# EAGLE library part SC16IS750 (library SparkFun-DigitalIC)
SPI/I2C/IrDA to UART

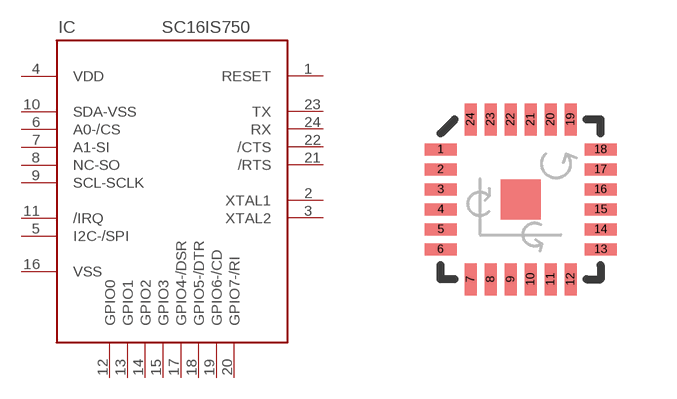
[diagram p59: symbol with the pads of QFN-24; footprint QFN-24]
Designator prefix IC

## SC16IS750  [QFN-24]
1  RESET
2  XTAL1
3  XTAL2
4  VDD
5  I2C-/SPI
6  A0-/CS
7  A1-SI
8  NC-SO
9  SCL-SCLK
10  SDA-VSS
11  /IRQ
12  GPIO0
13  GPIO1
14  GPIO2
15  GPIO3
16  VSS
17  GPIO4-/DSR
18  GPIO5-/DTR
19  GPIO6-/CD
20  GPIO7-/RI
21  /RTS
22  /CTS
23  TX
24  RX

## Footprint QFN-24 (pad centres in mm)
smd 0.8 x 0.3: 1 -2,1.25; 2 -2,0.75; 3 -2,0.25; 4 -2,-0.25; 5 -2,-0.75; 6 -2,-1.25; 13 2,-1.25; 14 2,-0.75; 15 2,-0.25; 16 2,0.25; 17 2,0.75; 18 2,1.25
smd 0.3 x 0.8: 7 -1.25,-2; 8 -0.75,-2; 9 -0.25,-2; 10 0.25,-2; 11 0.75,-2; 12 1.25,-2; 19 1.25,2; 20 0.75,2; 21 0.25,2; 22 -0.25,2; 23 -0.75,2; 24 -1.25,2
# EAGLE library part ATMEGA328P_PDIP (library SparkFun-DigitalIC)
uC used in the Arduino 32kb flash, 1k EEPROM, 2k SRAM This is the through-hole version of this chip.

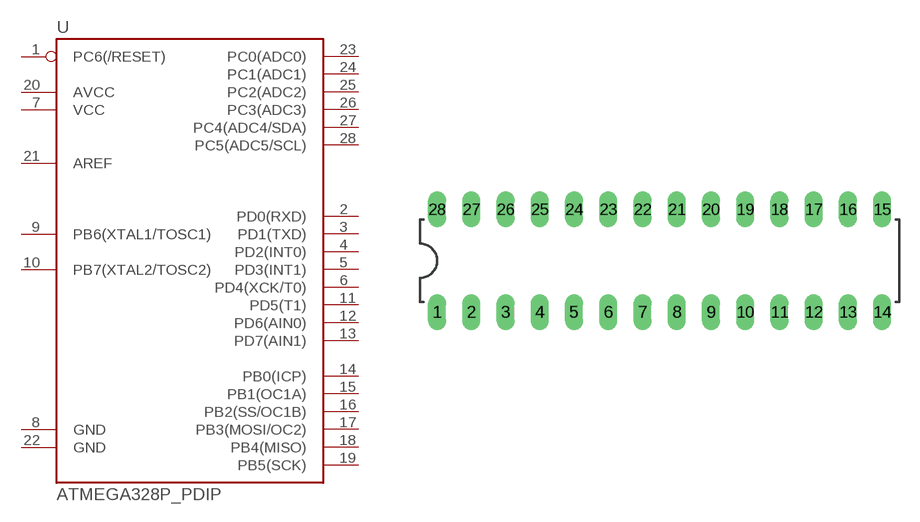
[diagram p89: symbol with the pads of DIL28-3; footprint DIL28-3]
Designator prefix U

## ATMEGA328P_PDIP  [DIL28-3]
1  PC6(/RESET)
2  PD0(RXD)
3  PD1(TXD)
4  PD2(INT0)
5  PD3(INT1)
6  PD4(XCK/T0)
7  VCC
8  GND
9  PB6(XTAL1/TOSC1)
10  PB7(XTAL2/TOSC2)
11  PD5(T1)
12  PD6(AIN0)
13  PD7(AIN1)
14  PB0(ICP)
15  PB1(OC1A)
16  PB2(SS/OC1B)
17  PB3(MOSI/OC2)
18  PB4(MISO)
19  PB5(SCK)
20  AVCC
21  AREF
22  GND
23  PC0(ADC0)
24  PC1(ADC1)
25  PC2(ADC2)
26  PC3(ADC3)
27  PC4(ADC4/SDA)
28  PC5(ADC5/SCL)

## Footprint DIL28-3 (pad centres in mm)
Standard 28-pin DIP package. IC needs to have legs bent before insertion.
drill 0.813 long: 1 -16.51,-3.81; 2 -13.97,-3.81; 3 -11.43,-3.81; 4 -8.89,-3.81; 5 -6.35,-3.81; 6 -3.81,-3.81; 7 -1.27,-3.81; 8 1.27,-3.81; 9 3.81,-3.81; 10 6.35,-3.81; 11 8.89,-3.81; 12 11.43,-3.81; 13 13.97,-3.81; 14 16.51,-3.81; 15 16.51,3.81; 16 13.97,3.81; 17 11.43,3.81; 18 8.89,3.81; 19 6.35,3.81; 20 3.81,3.81; 21 1.27,3.81; 22 -1.27,3.81; 23 -3.81,3.81; 24 -6.35,3.81; 25 -8.89,3.81; 26 -11.43,3.81; 27 -13.97,3.81; 28 -16.51,3.81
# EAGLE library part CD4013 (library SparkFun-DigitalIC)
Dual D-type Flip-Flop

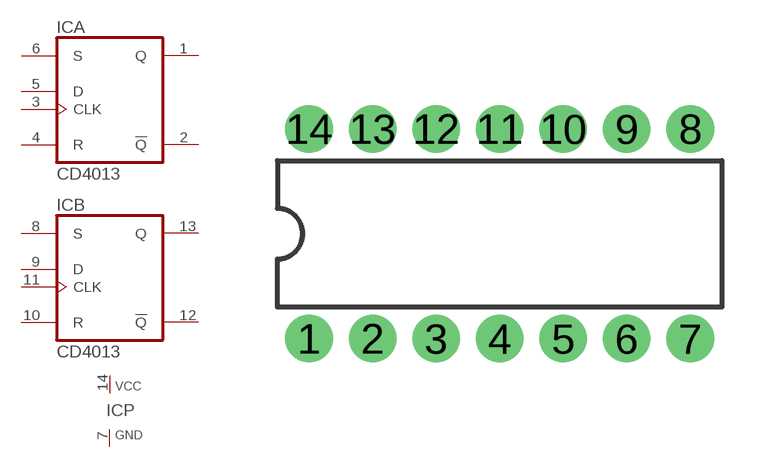
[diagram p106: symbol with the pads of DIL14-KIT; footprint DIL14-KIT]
Designator prefix IC; gates A=CD4013 B=CD4013 P=PWRN

## CD4013 (PROD_ID: IC-11896; VALUE: CD4013B)  [DIL14-KIT]
1  A:Q  out
2  A:!Q  out
3  A:CLK  in
4  A:R  in
5  A:D  in
6  A:S  in
7  P:GND  pwr
8  B:S  in
9  B:D  in
10  B:R  in
11  B:CLK  in
12  B:!Q  out
13  B:Q  out
14  P:VCC  pwr

## Footprint DIL14-KIT (pad centres in mm)
drill 0.864 pad 1.905: 1 -8.89,-4.191; 2 -6.35,-4.191; 3 -3.81,-4.191; 4 -1.27,-4.191; 5 1.27,-4.191; 6 3.81,-4.191; 7 6.35,-4.191; 8 6.35,4.191; 9 3.81,4.191; 10 1.27,4.191; 11 -1.27,4.191; 12 -3.81,4.191; 13 -6.35,4.191; 14 -8.89,4.191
